VERSION 5.7 ;
  NOWIREEXTENSIONATPIN ON ;
  DIVIDERCHAR "/" ;
  BUSBITCHARS "[]" ;
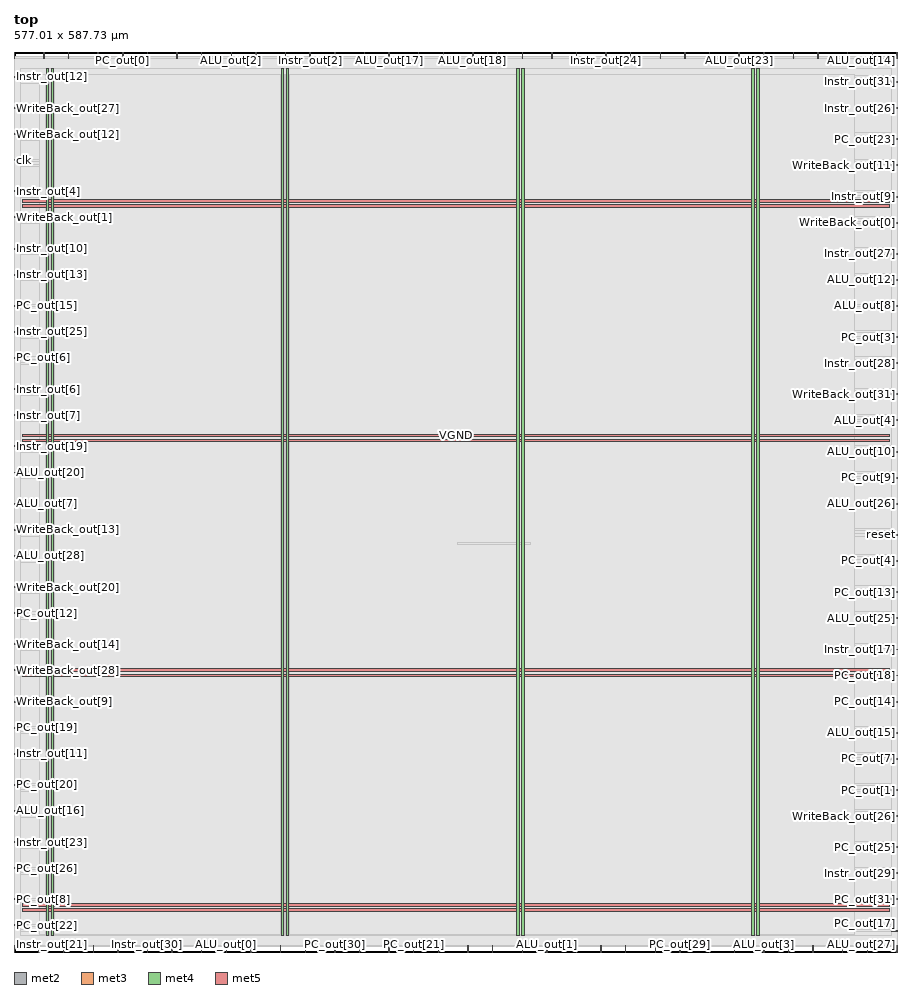
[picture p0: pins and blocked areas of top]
MACRO top
  CLASS BLOCK ;
  FOREIGN top ;
  ORIGIN 0.000 0.000 ;
  SIZE 577.010 BY 587.730 ;
  PIN ALU_out[0]
    DIRECTION OUTPUT TRISTATE ;
    USE SIGNAL ;
    ANTENNADIFFAREA 0.795200 ;
    PORT
      LAYER met2 ;
        RECT 138.550 0.000 138.830 4.000 ;
    END
  END ALU_out[0]
  PIN ALU_out[10]
    DIRECTION OUTPUT TRISTATE ;
    USE SIGNAL ;
    ANTENNADIFFAREA 0.445500 ;
    PORT
      LAYER met3 ;
        RECT 573.010 326.440 577.010 327.040 ;
    END
  END ALU_out[10]
  PIN ALU_out[11]
    DIRECTION OUTPUT TRISTATE ;
    USE SIGNAL ;
    ANTENNADIFFAREA 0.795200 ;
    PORT
      LAYER met2 ;
        RECT 541.050 0.000 541.330 4.000 ;
    END
  END ALU_out[11]
  PIN ALU_out[12]
    DIRECTION OUTPUT TRISTATE ;
    USE SIGNAL ;
    ANTENNADIFFAREA 0.445500 ;
    PORT
      LAYER met3 ;
        RECT 573.010 438.640 577.010 439.240 ;
    END
  END ALU_out[12]
  PIN ALU_out[13]
    DIRECTION OUTPUT TRISTATE ;
    USE SIGNAL ;
    ANTENNADIFFAREA 0.795200 ;
    PORT
      LAYER met2 ;
        RECT 244.810 0.000 245.090 4.000 ;
    END
  END ALU_out[13]
  PIN ALU_out[14]
    DIRECTION OUTPUT TRISTATE ;
    USE SIGNAL ;
    ANTENNADIFFAREA 0.795200 ;
    PORT
      LAYER met2 ;
        RECT 576.470 583.730 576.750 587.730 ;
    END
  END ALU_out[14]
  PIN ALU_out[15]
    DIRECTION OUTPUT TRISTATE ;
    USE SIGNAL ;
    ANTENNADIFFAREA 0.795200 ;
    PORT
      LAYER met3 ;
        RECT 573.010 142.840 577.010 143.440 ;
    END
  END ALU_out[15]
  PIN ALU_out[16]
    DIRECTION OUTPUT TRISTATE ;
    USE SIGNAL ;
    ANTENNADIFFAREA 0.795200 ;
    PORT
      LAYER met3 ;
        RECT 0.000 91.840 4.000 92.440 ;
    END
  END ALU_out[16]
  PIN ALU_out[17]
    DIRECTION OUTPUT TRISTATE ;
    USE SIGNAL ;
    ANTENNADIFFAREA 0.445500 ;
    PORT
      LAYER met2 ;
        RECT 244.810 583.730 245.090 587.730 ;
    END
  END ALU_out[17]
  PIN ALU_out[18]
    DIRECTION OUTPUT TRISTATE ;
    USE SIGNAL ;
    ANTENNADIFFAREA 0.445500 ;
    PORT
      LAYER met2 ;
        RECT 299.550 583.730 299.830 587.730 ;
    END
  END ALU_out[18]
  PIN ALU_out[19]
    DIRECTION OUTPUT TRISTATE ;
    USE SIGNAL ;
    ANTENNADIFFAREA 0.795200 ;
    PORT
      LAYER met2 ;
        RECT 508.850 583.730 509.130 587.730 ;
    END
  END ALU_out[19]
  PIN ALU_out[1]
    DIRECTION OUTPUT TRISTATE ;
    USE SIGNAL ;
    ANTENNADIFFAREA 0.795200 ;
    PORT
      LAYER met2 ;
        RECT 347.850 0.000 348.130 4.000 ;
    END
  END ALU_out[1]
  PIN ALU_out[20]
    DIRECTION OUTPUT TRISTATE ;
    USE SIGNAL ;
    ANTENNADIFFAREA 0.795200 ;
    PORT
      LAYER met3 ;
        RECT 0.000 312.840 4.000 313.440 ;
    END
  END ALU_out[20]
  PIN ALU_out[21]
    DIRECTION OUTPUT TRISTATE ;
    USE SIGNAL ;
    ANTENNADIFFAREA 0.445500 ;
    PORT
      LAYER met2 ;
        RECT 560.370 583.730 560.650 587.730 ;
    END
  END ALU_out[21]
  PIN ALU_out[22]
    DIRECTION OUTPUT TRISTATE ;
    USE SIGNAL ;
    ANTENNADIFFAREA 0.795200 ;
    PORT
      LAYER met2 ;
        RECT 54.830 583.730 55.110 587.730 ;
    END
  END ALU_out[22]
  PIN ALU_out[23]
    DIRECTION OUTPUT TRISTATE ;
    USE SIGNAL ;
    ANTENNADIFFAREA 0.445500 ;
    PORT
      LAYER met2 ;
        RECT 473.430 583.730 473.710 587.730 ;
    END
  END ALU_out[23]
  PIN ALU_out[24]
    DIRECTION OUTPUT TRISTATE ;
    USE SIGNAL ;
    ANTENNADIFFAREA 0.795200 ;
    PORT
      LAYER met2 ;
        RECT 228.710 583.730 228.990 587.730 ;
    END
  END ALU_out[24]
  PIN ALU_out[25]
    DIRECTION OUTPUT TRISTATE ;
    USE SIGNAL ;
    ANTENNADIFFAREA 0.445500 ;
    PORT
      LAYER met3 ;
        RECT 573.010 217.640 577.010 218.240 ;
    END
  END ALU_out[25]
  PIN ALU_out[26]
    DIRECTION OUTPUT TRISTATE ;
    USE SIGNAL ;
    ANTENNADIFFAREA 0.795200 ;
    PORT
      LAYER met3 ;
        RECT 573.010 292.440 577.010 293.040 ;
    END
  END ALU_out[26]
  PIN ALU_out[27]
    DIRECTION OUTPUT TRISTATE ;
    USE SIGNAL ;
    ANTENNADIFFAREA 0.795200 ;
    PORT
      LAYER met2 ;
        RECT 557.150 0.000 557.430 4.000 ;
    END
  END ALU_out[27]
  PIN ALU_out[28]
    DIRECTION OUTPUT TRISTATE ;
    USE SIGNAL ;
    ANTENNADIFFAREA 0.795200 ;
    PORT
      LAYER met3 ;
        RECT 0.000 258.440 4.000 259.040 ;
    END
  END ALU_out[28]
  PIN ALU_out[29]
    DIRECTION OUTPUT TRISTATE ;
    USE SIGNAL ;
    ANTENNADIFFAREA 0.795200 ;
    PORT
      LAYER met2 ;
        RECT 225.490 0.000 225.770 4.000 ;
    END
  END ALU_out[29]
  PIN ALU_out[2]
    DIRECTION OUTPUT TRISTATE ;
    USE SIGNAL ;
    ANTENNADIFFAREA 0.445500 ;
    PORT
      LAYER met2 ;
        RECT 141.770 583.730 142.050 587.730 ;
    END
  END ALU_out[2]
  PIN ALU_out[30]
    DIRECTION OUTPUT TRISTATE ;
    USE SIGNAL ;
    ANTENNADIFFAREA 0.795200 ;
    PORT
      LAYER met2 ;
        RECT 470.210 0.000 470.490 4.000 ;
    END
  END ALU_out[30]
  PIN ALU_out[31]
    DIRECTION OUTPUT TRISTATE ;
    USE SIGNAL ;
    ANTENNADIFFAREA 0.795200 ;
    PORT
      LAYER met2 ;
        RECT 154.650 0.000 154.930 4.000 ;
    END
  END ALU_out[31]
  PIN ALU_out[3]
    DIRECTION OUTPUT TRISTATE ;
    USE SIGNAL ;
    ANTENNADIFFAREA 0.795200 ;
    PORT
      LAYER met2 ;
        RECT 489.530 0.000 489.810 4.000 ;
    END
  END ALU_out[3]
  PIN ALU_out[4]
    DIRECTION OUTPUT TRISTATE ;
    USE SIGNAL ;
    ANTENNADIFFAREA 0.445500 ;
    PORT
      LAYER met3 ;
        RECT 573.010 346.840 577.010 347.440 ;
    END
  END ALU_out[4]
  PIN ALU_out[5]
    DIRECTION OUTPUT TRISTATE ;
    USE SIGNAL ;
    ANTENNADIFFAREA 0.795200 ;
    PORT
      LAYER met2 ;
        RECT 367.170 0.000 367.450 4.000 ;
    END
  END ALU_out[5]
  PIN ALU_out[6]
    DIRECTION OUTPUT TRISTATE ;
    USE SIGNAL ;
    ANTENNADIFFAREA 0.795200 ;
    PORT
      LAYER met2 ;
        RECT 418.690 0.000 418.970 4.000 ;
    END
  END ALU_out[6]
  PIN ALU_out[7]
    DIRECTION OUTPUT TRISTATE ;
    USE SIGNAL ;
    ANTENNADIFFAREA 0.795200 ;
    PORT
      LAYER met3 ;
        RECT 0.000 292.440 4.000 293.040 ;
    END
  END ALU_out[7]
  PIN ALU_out[8]
    DIRECTION OUTPUT TRISTATE ;
    USE SIGNAL ;
    ANTENNADIFFAREA 0.445500 ;
    PORT
      LAYER met3 ;
        RECT 573.010 421.640 577.010 422.240 ;
    END
  END ALU_out[8]
  PIN ALU_out[9]
    DIRECTION OUTPUT TRISTATE ;
    USE SIGNAL ;
    ANTENNADIFFAREA 0.795200 ;
    PORT
      LAYER met2 ;
        RECT 157.870 583.730 158.150 587.730 ;
    END
  END ALU_out[9]
  PIN Instr_out[0]
    DIRECTION OUTPUT TRISTATE ;
    USE SIGNAL ;
    PORT
      LAYER met2 ;
        RECT 576.470 0.000 576.750 4.000 ;
    END
  END Instr_out[0]
  PIN Instr_out[10]
    DIRECTION OUTPUT TRISTATE ;
    USE SIGNAL ;
    PORT
      LAYER met3 ;
        RECT 0.000 459.040 4.000 459.640 ;
    END
  END Instr_out[10]
  PIN Instr_out[11]
    DIRECTION OUTPUT TRISTATE ;
    USE SIGNAL ;
    PORT
      LAYER met3 ;
        RECT 0.000 129.240 4.000 129.840 ;
    END
  END Instr_out[11]
  PIN Instr_out[12]
    DIRECTION OUTPUT TRISTATE ;
    USE SIGNAL ;
    ANTENNADIFFAREA 0.795200 ;
    PORT
      LAYER met3 ;
        RECT 0.000 571.240 4.000 571.840 ;
    END
  END Instr_out[12]
  PIN Instr_out[13]
    DIRECTION OUTPUT TRISTATE ;
    USE SIGNAL ;
    ANTENNADIFFAREA 0.795200 ;
    PORT
      LAYER met3 ;
        RECT 0.000 442.040 4.000 442.640 ;
    END
  END Instr_out[13]
  PIN Instr_out[14]
    DIRECTION OUTPUT TRISTATE ;
    USE SIGNAL ;
    ANTENNADIFFAREA 0.795200 ;
    PORT
      LAYER met2 ;
        RECT 544.270 583.730 544.550 587.730 ;
    END
  END Instr_out[14]
  PIN Instr_out[15]
    DIRECTION OUTPUT TRISTATE ;
    USE SIGNAL ;
    ANTENNADIFFAREA 0.795200 ;
    PORT
      LAYER met2 ;
        RECT 489.530 583.730 489.810 587.730 ;
    END
  END Instr_out[15]
  PIN Instr_out[16]
    DIRECTION OUTPUT TRISTATE ;
    USE SIGNAL ;
    ANTENNADIFFAREA 0.795200 ;
    PORT
      LAYER met2 ;
        RECT 122.450 583.730 122.730 587.730 ;
    END
  END Instr_out[16]
  PIN Instr_out[17]
    DIRECTION OUTPUT TRISTATE ;
    USE SIGNAL ;
    PORT
      LAYER met3 ;
        RECT 573.010 197.240 577.010 197.840 ;
    END
  END Instr_out[17]
  PIN Instr_out[18]
    DIRECTION OUTPUT TRISTATE ;
    USE SIGNAL ;
    PORT
      LAYER met2 ;
        RECT 173.970 0.000 174.250 4.000 ;
    END
  END Instr_out[18]
  PIN Instr_out[19]
    DIRECTION OUTPUT TRISTATE ;
    USE SIGNAL ;
    PORT
      LAYER met3 ;
        RECT 0.000 329.840 4.000 330.440 ;
    END
  END Instr_out[19]
  PIN Instr_out[1]
    DIRECTION OUTPUT TRISTATE ;
    USE SIGNAL ;
    PORT
      LAYER met2 ;
        RECT 87.030 583.730 87.310 587.730 ;
    END
  END Instr_out[1]
  PIN Instr_out[20]
    DIRECTION OUTPUT TRISTATE ;
    USE SIGNAL ;
    ANTENNADIFFAREA 0.795200 ;
    PORT
      LAYER met2 ;
        RECT 315.650 583.730 315.930 587.730 ;
    END
  END Instr_out[20]
  PIN Instr_out[21]
    DIRECTION OUTPUT TRISTATE ;
    USE SIGNAL ;
    ANTENNADIFFAREA 0.795200 ;
    PORT
      LAYER met2 ;
        RECT 16.190 0.000 16.470 4.000 ;
    END
  END Instr_out[21]
  PIN Instr_out[22]
    DIRECTION OUTPUT TRISTATE ;
    USE SIGNAL ;
    ANTENNADIFFAREA 0.445500 ;
    PORT
      LAYER met2 ;
        RECT 402.590 583.730 402.870 587.730 ;
    END
  END Instr_out[22]
  PIN Instr_out[23]
    DIRECTION OUTPUT TRISTATE ;
    USE SIGNAL ;
    ANTENNADIFFAREA 0.795200 ;
    PORT
      LAYER met3 ;
        RECT 0.000 71.440 4.000 72.040 ;
    END
  END Instr_out[23]
  PIN Instr_out[24]
    DIRECTION OUTPUT TRISTATE ;
    USE SIGNAL ;
    PORT
      LAYER met2 ;
        RECT 386.490 583.730 386.770 587.730 ;
    END
  END Instr_out[24]
  PIN Instr_out[25]
    DIRECTION OUTPUT TRISTATE ;
    USE SIGNAL ;
    PORT
      LAYER met3 ;
        RECT 0.000 404.640 4.000 405.240 ;
    END
  END Instr_out[25]
  PIN Instr_out[26]
    DIRECTION OUTPUT TRISTATE ;
    USE SIGNAL ;
    PORT
      LAYER met3 ;
        RECT 573.010 550.840 577.010 551.440 ;
    END
  END Instr_out[26]
  PIN Instr_out[27]
    DIRECTION OUTPUT TRISTATE ;
    USE SIGNAL ;
    PORT
      LAYER met3 ;
        RECT 573.010 455.640 577.010 456.240 ;
    END
  END Instr_out[27]
  PIN Instr_out[28]
    DIRECTION OUTPUT TRISTATE ;
    USE SIGNAL ;
    PORT
      LAYER met3 ;
        RECT 573.010 384.240 577.010 384.840 ;
    END
  END Instr_out[28]
  PIN Instr_out[29]
    DIRECTION OUTPUT TRISTATE ;
    USE SIGNAL ;
    PORT
      LAYER met3 ;
        RECT 573.010 51.040 577.010 51.640 ;
    END
  END Instr_out[29]
  PIN Instr_out[2]
    DIRECTION OUTPUT TRISTATE ;
    USE SIGNAL ;
    PORT
      LAYER met2 ;
        RECT 193.290 583.730 193.570 587.730 ;
    END
  END Instr_out[2]
  PIN Instr_out[30]
    DIRECTION OUTPUT TRISTATE ;
    USE SIGNAL ;
    ANTENNADIFFAREA 0.795200 ;
    PORT
      LAYER met2 ;
        RECT 87.030 0.000 87.310 4.000 ;
    END
  END Instr_out[30]
  PIN Instr_out[31]
    DIRECTION OUTPUT TRISTATE ;
    USE SIGNAL ;
    PORT
      LAYER met3 ;
        RECT 573.010 567.840 577.010 568.440 ;
    END
  END Instr_out[31]
  PIN Instr_out[3]
    DIRECTION OUTPUT TRISTATE ;
    USE SIGNAL ;
    PORT
      LAYER met2 ;
        RECT 296.330 0.000 296.610 4.000 ;
    END
  END Instr_out[3]
  PIN Instr_out[4]
    DIRECTION OUTPUT TRISTATE ;
    USE SIGNAL ;
    ANTENNADIFFAREA 0.795200 ;
    PORT
      LAYER met3 ;
        RECT 0.000 496.440 4.000 497.040 ;
    END
  END Instr_out[4]
  PIN Instr_out[5]
    DIRECTION OUTPUT TRISTATE ;
    USE SIGNAL ;
    ANTENNADIFFAREA 0.795200 ;
    PORT
      LAYER met2 ;
        RECT 351.070 583.730 351.350 587.730 ;
    END
  END Instr_out[5]
  PIN Instr_out[6]
    DIRECTION OUTPUT TRISTATE ;
    USE SIGNAL ;
    ANTENNADIFFAREA 0.795200 ;
    PORT
      LAYER met3 ;
        RECT 0.000 367.240 4.000 367.840 ;
    END
  END Instr_out[6]
  PIN Instr_out[7]
    DIRECTION OUTPUT TRISTATE ;
    USE SIGNAL ;
    ANTENNADIFFAREA 0.795200 ;
    PORT
      LAYER met3 ;
        RECT 0.000 350.240 4.000 350.840 ;
    END
  END Instr_out[7]
  PIN Instr_out[8]
    DIRECTION OUTPUT TRISTATE ;
    USE SIGNAL ;
    ANTENNADIFFAREA 0.795200 ;
    PORT
      LAYER met2 ;
        RECT 35.510 583.730 35.790 587.730 ;
    END
  END Instr_out[8]
  PIN Instr_out[9]
    DIRECTION OUTPUT TRISTATE ;
    USE SIGNAL ;
    ANTENNADIFFAREA 0.445500 ;
    PORT
      LAYER met3 ;
        RECT 573.010 493.040 577.010 493.640 ;
    END
  END Instr_out[9]
  PIN PC_out[0]
    DIRECTION OUTPUT TRISTATE ;
    USE SIGNAL ;
    ANTENNADIFFAREA 0.445500 ;
    PORT
      LAYER met2 ;
        RECT 70.930 583.730 71.210 587.730 ;
    END
  END PC_out[0]
  PIN PC_out[10]
    DIRECTION OUTPUT TRISTATE ;
    USE SIGNAL ;
    ANTENNADIFFAREA 0.445500 ;
    PORT
      LAYER met2 ;
        RECT 209.390 583.730 209.670 587.730 ;
    END
  END PC_out[10]
  PIN PC_out[11]
    DIRECTION OUTPUT TRISTATE ;
    USE SIGNAL ;
    ANTENNADIFFAREA 0.445500 ;
    PORT
      LAYER met2 ;
        RECT 264.130 583.730 264.410 587.730 ;
    END
  END PC_out[11]
  PIN PC_out[12]
    DIRECTION OUTPUT TRISTATE ;
    USE SIGNAL ;
    ANTENNADIFFAREA 0.795200 ;
    PORT
      LAYER met3 ;
        RECT 0.000 221.040 4.000 221.640 ;
    END
  END PC_out[12]
  PIN PC_out[13]
    DIRECTION OUTPUT TRISTATE ;
    USE SIGNAL ;
    ANTENNADIFFAREA 0.445500 ;
    PORT
      LAYER met3 ;
        RECT 573.010 234.640 577.010 235.240 ;
    END
  END PC_out[13]
  PIN PC_out[14]
    DIRECTION OUTPUT TRISTATE ;
    USE SIGNAL ;
    ANTENNADIFFAREA 0.445500 ;
    PORT
      LAYER met3 ;
        RECT 573.010 163.240 577.010 163.840 ;
    END
  END PC_out[14]
  PIN PC_out[15]
    DIRECTION OUTPUT TRISTATE ;
    USE SIGNAL ;
    ANTENNADIFFAREA 0.795200 ;
    PORT
      LAYER met3 ;
        RECT 0.000 421.640 4.000 422.240 ;
    END
  END PC_out[15]
  PIN PC_out[16]
    DIRECTION OUTPUT TRISTATE ;
    USE SIGNAL ;
    ANTENNADIFFAREA 0.795200 ;
    PORT
      LAYER met2 ;
        RECT 51.610 0.000 51.890 4.000 ;
    END
  END PC_out[16]
  PIN PC_out[17]
    DIRECTION OUTPUT TRISTATE ;
    USE SIGNAL ;
    ANTENNADIFFAREA 0.445500 ;
    PORT
      LAYER met3 ;
        RECT 573.010 13.640 577.010 14.240 ;
    END
  END PC_out[17]
  PIN PC_out[18]
    DIRECTION OUTPUT TRISTATE ;
    USE SIGNAL ;
    ANTENNADIFFAREA 0.445500 ;
    PORT
      LAYER met3 ;
        RECT 573.010 180.240 577.010 180.840 ;
    END
  END PC_out[18]
  PIN PC_out[19]
    DIRECTION OUTPUT TRISTATE ;
    USE SIGNAL ;
    ANTENNADIFFAREA 0.795200 ;
    PORT
      LAYER met3 ;
        RECT 0.000 146.240 4.000 146.840 ;
    END
  END PC_out[19]
  PIN PC_out[1]
    DIRECTION OUTPUT TRISTATE ;
    USE SIGNAL ;
    ANTENNADIFFAREA 0.445500 ;
    PORT
      LAYER met3 ;
        RECT 573.010 105.440 577.010 106.040 ;
    END
  END PC_out[1]
  PIN PC_out[20]
    DIRECTION OUTPUT TRISTATE ;
    USE SIGNAL ;
    ANTENNADIFFAREA 0.795200 ;
    PORT
      LAYER met3 ;
        RECT 0.000 108.840 4.000 109.440 ;
    END
  END PC_out[20]
  PIN PC_out[21]
    DIRECTION OUTPUT TRISTATE ;
    USE SIGNAL ;
    ANTENNADIFFAREA 0.795200 ;
    PORT
      LAYER met2 ;
        RECT 260.910 0.000 261.190 4.000 ;
    END
  END PC_out[21]
  PIN PC_out[22]
    DIRECTION OUTPUT TRISTATE ;
    USE SIGNAL ;
    ANTENNADIFFAREA 0.795200 ;
    PORT
      LAYER met3 ;
        RECT 0.000 17.040 4.000 17.640 ;
    END
  END PC_out[22]
  PIN PC_out[23]
    DIRECTION OUTPUT TRISTATE ;
    USE SIGNAL ;
    ANTENNADIFFAREA 0.795200 ;
    PORT
      LAYER met3 ;
        RECT 573.010 530.440 577.010 531.040 ;
    END
  END PC_out[23]
  PIN PC_out[24]
    DIRECTION OUTPUT TRISTATE ;
    USE SIGNAL ;
    ANTENNADIFFAREA 0.795200 ;
    PORT
      LAYER met2 ;
        RECT 122.450 0.000 122.730 4.000 ;
    END
  END PC_out[24]
  PIN PC_out[25]
    DIRECTION OUTPUT TRISTATE ;
    USE SIGNAL ;
    ANTENNADIFFAREA 0.795200 ;
    PORT
      LAYER met3 ;
        RECT 573.010 68.040 577.010 68.640 ;
    END
  END PC_out[25]
  PIN PC_out[26]
    DIRECTION OUTPUT TRISTATE ;
    USE SIGNAL ;
    ANTENNADIFFAREA 0.795200 ;
    PORT
      LAYER met3 ;
        RECT 0.000 54.440 4.000 55.040 ;
    END
  END PC_out[26]
  PIN PC_out[27]
    DIRECTION OUTPUT TRISTATE ;
    USE SIGNAL ;
    ANTENNADIFFAREA 0.795200 ;
    PORT
      LAYER met2 ;
        RECT 521.730 0.000 522.010 4.000 ;
    END
  END PC_out[27]
  PIN PC_out[28]
    DIRECTION OUTPUT TRISTATE ;
    USE SIGNAL ;
    ANTENNADIFFAREA 0.445500 ;
    PORT
      LAYER met2 ;
        RECT 280.230 583.730 280.510 587.730 ;
    END
  END PC_out[28]
  PIN PC_out[29]
    DIRECTION OUTPUT TRISTATE ;
    USE SIGNAL ;
    ANTENNADIFFAREA 0.795200 ;
    PORT
      LAYER met2 ;
        RECT 434.790 0.000 435.070 4.000 ;
    END
  END PC_out[29]
  PIN PC_out[2]
    DIRECTION OUTPUT TRISTATE ;
    USE SIGNAL ;
    ANTENNADIFFAREA 0.795200 ;
    PORT
      LAYER met2 ;
        RECT 67.710 0.000 67.990 4.000 ;
    END
  END PC_out[2]
  PIN PC_out[30]
    DIRECTION OUTPUT TRISTATE ;
    USE SIGNAL ;
    ANTENNADIFFAREA 0.795200 ;
    PORT
      LAYER met2 ;
        RECT 209.390 0.000 209.670 4.000 ;
    END
  END PC_out[30]
  PIN PC_out[31]
    DIRECTION OUTPUT TRISTATE ;
    USE SIGNAL ;
    ANTENNADIFFAREA 0.795200 ;
    PORT
      LAYER met3 ;
        RECT 573.010 34.040 577.010 34.640 ;
    END
  END PC_out[31]
  PIN PC_out[3]
    DIRECTION OUTPUT TRISTATE ;
    USE SIGNAL ;
    ANTENNADIFFAREA 0.445500 ;
    PORT
      LAYER met3 ;
        RECT 573.010 401.240 577.010 401.840 ;
    END
  END PC_out[3]
  PIN PC_out[4]
    DIRECTION OUTPUT TRISTATE ;
    USE SIGNAL ;
    ANTENNADIFFAREA 0.445500 ;
    PORT
      LAYER met3 ;
        RECT 573.010 255.040 577.010 255.640 ;
    END
  END PC_out[4]
  PIN PC_out[5]
    DIRECTION OUTPUT TRISTATE ;
    USE SIGNAL ;
    ANTENNADIFFAREA 0.795200 ;
    PORT
      LAYER met2 ;
        RECT 454.110 0.000 454.390 4.000 ;
    END
  END PC_out[5]
  PIN PC_out[6]
    DIRECTION OUTPUT TRISTATE ;
    USE SIGNAL ;
    ANTENNADIFFAREA 0.795200 ;
    PORT
      LAYER met3 ;
        RECT 0.000 387.640 4.000 388.240 ;
    END
  END PC_out[6]
  PIN PC_out[7]
    DIRECTION OUTPUT TRISTATE ;
    USE SIGNAL ;
    ANTENNADIFFAREA 0.445500 ;
    PORT
      LAYER met3 ;
        RECT 573.010 125.840 577.010 126.440 ;
    END
  END PC_out[7]
  PIN PC_out[8]
    DIRECTION OUTPUT TRISTATE ;
    USE SIGNAL ;
    ANTENNADIFFAREA 0.795200 ;
    PORT
      LAYER met3 ;
        RECT 0.000 34.040 4.000 34.640 ;
    END
  END PC_out[8]
  PIN PC_out[9]
    DIRECTION OUTPUT TRISTATE ;
    USE SIGNAL ;
    ANTENNADIFFAREA 0.795200 ;
    PORT
      LAYER met3 ;
        RECT 573.010 309.440 577.010 310.040 ;
    END
  END PC_out[9]
  PIN VGND
    DIRECTION INOUT ;
    USE GROUND ;
    PORT
      LAYER met4 ;
        RECT 24.340 10.640 25.940 576.880 ;
    END
    PORT
      LAYER met4 ;
        RECT 177.940 10.640 179.540 576.880 ;
    END
    PORT
      LAYER met4 ;
        RECT 331.540 10.640 333.140 576.880 ;
    END
    PORT
      LAYER met4 ;
        RECT 485.140 10.640 486.740 576.880 ;
    END
    PORT
      LAYER met5 ;
        RECT 5.280 30.030 571.560 31.630 ;
    END
    PORT
      LAYER met5 ;
        RECT 5.280 183.210 571.560 184.810 ;
    END
    PORT
      LAYER met5 ;
        RECT 5.280 336.390 571.560 337.990 ;
    END
    PORT
      LAYER met5 ;
        RECT 5.280 489.570 571.560 491.170 ;
    END
  END VGND
  PIN VPWR
    DIRECTION INOUT ;
    USE POWER ;
    PORT
      LAYER met4 ;
        RECT 21.040 10.640 22.640 576.880 ;
    END
    PORT
      LAYER met4 ;
        RECT 174.640 10.640 176.240 576.880 ;
    END
    PORT
      LAYER met4 ;
        RECT 328.240 10.640 329.840 576.880 ;
    END
    PORT
      LAYER met4 ;
        RECT 481.840 10.640 483.440 576.880 ;
    END
    PORT
      LAYER met5 ;
        RECT 5.280 26.730 571.560 28.330 ;
    END
    PORT
      LAYER met5 ;
        RECT 5.280 179.910 571.560 181.510 ;
    END
    PORT
      LAYER met5 ;
        RECT 5.280 333.090 571.560 334.690 ;
    END
    PORT
      LAYER met5 ;
        RECT 5.280 486.270 571.560 487.870 ;
    END
  END VPWR
  PIN WriteBack_out[0]
    DIRECTION OUTPUT TRISTATE ;
    USE SIGNAL ;
    ANTENNADIFFAREA 0.445500 ;
    PORT
      LAYER met3 ;
        RECT 573.010 476.040 577.010 476.640 ;
    END
  END WriteBack_out[0]
  PIN WriteBack_out[10]
    DIRECTION OUTPUT TRISTATE ;
    USE SIGNAL ;
    ANTENNADIFFAREA 0.795200 ;
    PORT
      LAYER met2 ;
        RECT 505.630 0.000 505.910 4.000 ;
    END
  END WriteBack_out[10]
  PIN WriteBack_out[11]
    DIRECTION OUTPUT TRISTATE ;
    USE SIGNAL ;
    ANTENNADIFFAREA 0.445500 ;
    PORT
      LAYER met3 ;
        RECT 573.010 513.440 577.010 514.040 ;
    END
  END WriteBack_out[11]
  PIN WriteBack_out[12]
    DIRECTION OUTPUT TRISTATE ;
    USE SIGNAL ;
    ANTENNADIFFAREA 0.795200 ;
    PORT
      LAYER met3 ;
        RECT 0.000 533.840 4.000 534.440 ;
    END
  END WriteBack_out[12]
  PIN WriteBack_out[13]
    DIRECTION OUTPUT TRISTATE ;
    USE SIGNAL ;
    ANTENNADIFFAREA 0.795200 ;
    PORT
      LAYER met3 ;
        RECT 0.000 275.440 4.000 276.040 ;
    END
  END WriteBack_out[13]
  PIN WriteBack_out[14]
    DIRECTION OUTPUT TRISTATE ;
    USE SIGNAL ;
    ANTENNADIFFAREA 0.795200 ;
    PORT
      LAYER met3 ;
        RECT 0.000 200.640 4.000 201.240 ;
    END
  END WriteBack_out[14]
  PIN WriteBack_out[15]
    DIRECTION OUTPUT TRISTATE ;
    USE SIGNAL ;
    ANTENNADIFFAREA 0.795200 ;
    PORT
      LAYER met2 ;
        RECT 0.090 0.000 0.370 4.000 ;
    END
  END WriteBack_out[15]
  PIN WriteBack_out[16]
    DIRECTION OUTPUT TRISTATE ;
    USE SIGNAL ;
    ANTENNADIFFAREA 0.795200 ;
    PORT
      LAYER met2 ;
        RECT 383.270 0.000 383.550 4.000 ;
    END
  END WriteBack_out[16]
  PIN WriteBack_out[17]
    DIRECTION OUTPUT TRISTATE ;
    USE SIGNAL ;
    ANTENNADIFFAREA 0.795200 ;
    PORT
      LAYER met2 ;
        RECT 0.090 583.730 0.370 587.730 ;
    END
  END WriteBack_out[17]
  PIN WriteBack_out[18]
    DIRECTION OUTPUT TRISTATE ;
    USE SIGNAL ;
    ANTENNADIFFAREA 0.445500 ;
    PORT
      LAYER met2 ;
        RECT 177.190 583.730 177.470 587.730 ;
    END
  END WriteBack_out[18]
  PIN WriteBack_out[19]
    DIRECTION OUTPUT TRISTATE ;
    USE SIGNAL ;
    ANTENNADIFFAREA 0.445500 ;
    PORT
      LAYER met2 ;
        RECT 367.170 583.730 367.450 587.730 ;
    END
  END WriteBack_out[19]
  PIN WriteBack_out[1]
    DIRECTION OUTPUT TRISTATE ;
    USE SIGNAL ;
    ANTENNADIFFAREA 0.795200 ;
    PORT
      LAYER met3 ;
        RECT 0.000 479.440 4.000 480.040 ;
    END
  END WriteBack_out[1]
  PIN WriteBack_out[20]
    DIRECTION OUTPUT TRISTATE ;
    USE SIGNAL ;
    ANTENNADIFFAREA 0.795200 ;
    PORT
      LAYER met3 ;
        RECT 0.000 238.040 4.000 238.640 ;
    END
  END WriteBack_out[20]
  PIN WriteBack_out[21]
    DIRECTION OUTPUT TRISTATE ;
    USE SIGNAL ;
    ANTENNADIFFAREA 0.795200 ;
    PORT
      LAYER met2 ;
        RECT 32.290 0.000 32.570 4.000 ;
    END
  END WriteBack_out[21]
  PIN WriteBack_out[22]
    DIRECTION OUTPUT TRISTATE ;
    USE SIGNAL ;
    ANTENNADIFFAREA 0.795200 ;
    PORT
      LAYER met2 ;
        RECT 454.110 583.730 454.390 587.730 ;
    END
  END WriteBack_out[22]
  PIN WriteBack_out[23]
    DIRECTION OUTPUT TRISTATE ;
    USE SIGNAL ;
    ANTENNADIFFAREA 0.795200 ;
    PORT
      LAYER met2 ;
        RECT 331.750 583.730 332.030 587.730 ;
    END
  END WriteBack_out[23]
  PIN WriteBack_out[24]
    DIRECTION OUTPUT TRISTATE ;
    USE SIGNAL ;
    ANTENNADIFFAREA 0.795200 ;
    PORT
      LAYER met2 ;
        RECT 277.010 0.000 277.290 4.000 ;
    END
  END WriteBack_out[24]
  PIN WriteBack_out[25]
    DIRECTION OUTPUT TRISTATE ;
    USE SIGNAL ;
    ANTENNADIFFAREA 0.795200 ;
    PORT
      LAYER met2 ;
        RECT 524.950 583.730 525.230 587.730 ;
    END
  END WriteBack_out[25]
  PIN WriteBack_out[26]
    DIRECTION OUTPUT TRISTATE ;
    USE SIGNAL ;
    ANTENNADIFFAREA 0.795200 ;
    PORT
      LAYER met3 ;
        RECT 573.010 88.440 577.010 89.040 ;
    END
  END WriteBack_out[26]
  PIN WriteBack_out[27]
    DIRECTION OUTPUT TRISTATE ;
    USE SIGNAL ;
    ANTENNADIFFAREA 0.795200 ;
    PORT
      LAYER met3 ;
        RECT 0.000 550.840 4.000 551.440 ;
    END
  END WriteBack_out[27]
  PIN WriteBack_out[28]
    DIRECTION OUTPUT TRISTATE ;
    USE SIGNAL ;
    ANTENNADIFFAREA 0.795200 ;
    PORT
      LAYER met3 ;
        RECT 0.000 183.640 4.000 184.240 ;
    END
  END WriteBack_out[28]
  PIN WriteBack_out[29]
    DIRECTION OUTPUT TRISTATE ;
    USE SIGNAL ;
    ANTENNADIFFAREA 0.795200 ;
    PORT
      LAYER met2 ;
        RECT 103.130 0.000 103.410 4.000 ;
    END
  END WriteBack_out[29]
  PIN WriteBack_out[2]
    DIRECTION OUTPUT TRISTATE ;
    USE SIGNAL ;
    ANTENNADIFFAREA 0.795200 ;
    PORT
      LAYER met2 ;
        RECT 190.070 0.000 190.350 4.000 ;
    END
  END WriteBack_out[2]
  PIN WriteBack_out[30]
    DIRECTION OUTPUT TRISTATE ;
    USE SIGNAL ;
    ANTENNADIFFAREA 0.891000 ;
    PORT
      LAYER met2 ;
        RECT 312.430 0.000 312.710 4.000 ;
    END
  END WriteBack_out[30]
  PIN WriteBack_out[31]
    DIRECTION OUTPUT TRISTATE ;
    USE SIGNAL ;
    ANTENNADIFFAREA 0.445500 ;
    PORT
      LAYER met3 ;
        RECT 573.010 363.840 577.010 364.440 ;
    END
  END WriteBack_out[31]
  PIN WriteBack_out[3]
    DIRECTION OUTPUT TRISTATE ;
    USE SIGNAL ;
    ANTENNADIFFAREA 0.795200 ;
    PORT
      LAYER met2 ;
        RECT 331.750 0.000 332.030 4.000 ;
    END
  END WriteBack_out[3]
  PIN WriteBack_out[4]
    DIRECTION OUTPUT TRISTATE ;
    USE SIGNAL ;
    ANTENNADIFFAREA 0.445500 ;
    PORT
      LAYER met2 ;
        RECT 438.010 583.730 438.290 587.730 ;
    END
  END WriteBack_out[4]
  PIN WriteBack_out[5]
    DIRECTION OUTPUT TRISTATE ;
    USE SIGNAL ;
    ANTENNADIFFAREA 0.445500 ;
    PORT
      LAYER met2 ;
        RECT 421.910 583.730 422.190 587.730 ;
    END
  END WriteBack_out[5]
  PIN WriteBack_out[6]
    DIRECTION OUTPUT TRISTATE ;
    USE SIGNAL ;
    ANTENNADIFFAREA 0.795200 ;
    PORT
      LAYER met2 ;
        RECT 19.410 583.730 19.690 587.730 ;
    END
  END WriteBack_out[6]
  PIN WriteBack_out[7]
    DIRECTION OUTPUT TRISTATE ;
    USE SIGNAL ;
    ANTENNADIFFAREA 0.445500 ;
    PORT
      LAYER met2 ;
        RECT 106.350 583.730 106.630 587.730 ;
    END
  END WriteBack_out[7]
  PIN WriteBack_out[8]
    DIRECTION OUTPUT TRISTATE ;
    USE SIGNAL ;
    ANTENNADIFFAREA 0.795200 ;
    PORT
      LAYER met2 ;
        RECT 399.370 0.000 399.650 4.000 ;
    END
  END WriteBack_out[8]
  PIN WriteBack_out[9]
    DIRECTION OUTPUT TRISTATE ;
    USE SIGNAL ;
    ANTENNADIFFAREA 0.795200 ;
    PORT
      LAYER met3 ;
        RECT 0.000 163.240 4.000 163.840 ;
    END
  END WriteBack_out[9]
  PIN clk
    DIRECTION INPUT ;
    USE SIGNAL ;
    ANTENNAGATEAREA 1.286700 ;
    ANTENNADIFFAREA 0.434700 ;
    PORT
      LAYER met3 ;
        RECT 0.000 516.840 4.000 517.440 ;
    END
  END clk
  PIN reset
    DIRECTION INPUT ;
    USE SIGNAL ;
    ANTENNAGATEAREA 0.196500 ;
    PORT
      LAYER met3 ;
        RECT 573.010 272.040 577.010 272.640 ;
    END
  END reset
  OBS
      LAYER li1 ;
        RECT 5.520 10.795 571.320 576.725 ;
      LAYER met1 ;
        RECT 0.070 8.200 576.770 576.880 ;
      LAYER met2 ;
        RECT 0.650 583.450 19.130 584.530 ;
        RECT 19.970 583.450 35.230 584.530 ;
        RECT 36.070 583.450 54.550 584.530 ;
        RECT 55.390 583.450 70.650 584.530 ;
        RECT 71.490 583.450 86.750 584.530 ;
        RECT 87.590 583.450 106.070 584.530 ;
        RECT 106.910 583.450 122.170 584.530 ;
        RECT 123.010 583.450 141.490 584.530 ;
        RECT 142.330 583.450 157.590 584.530 ;
        RECT 158.430 583.450 176.910 584.530 ;
        RECT 177.750 583.450 193.010 584.530 ;
        RECT 193.850 583.450 209.110 584.530 ;
        RECT 209.950 583.450 228.430 584.530 ;
        RECT 229.270 583.450 244.530 584.530 ;
        RECT 245.370 583.450 263.850 584.530 ;
        RECT 264.690 583.450 279.950 584.530 ;
        RECT 280.790 583.450 299.270 584.530 ;
        RECT 300.110 583.450 315.370 584.530 ;
        RECT 316.210 583.450 331.470 584.530 ;
        RECT 332.310 583.450 350.790 584.530 ;
        RECT 351.630 583.450 366.890 584.530 ;
        RECT 367.730 583.450 386.210 584.530 ;
        RECT 387.050 583.450 402.310 584.530 ;
        RECT 403.150 583.450 421.630 584.530 ;
        RECT 422.470 583.450 437.730 584.530 ;
        RECT 438.570 583.450 453.830 584.530 ;
        RECT 454.670 583.450 473.150 584.530 ;
        RECT 473.990 583.450 489.250 584.530 ;
        RECT 490.090 583.450 508.570 584.530 ;
        RECT 509.410 583.450 524.670 584.530 ;
        RECT 525.510 583.450 543.990 584.530 ;
        RECT 544.830 583.450 560.090 584.530 ;
        RECT 560.930 583.450 576.190 584.530 ;
        RECT 0.100 4.280 576.740 583.450 ;
        RECT 0.650 3.670 15.910 4.280 ;
        RECT 16.750 3.670 32.010 4.280 ;
        RECT 32.850 3.670 51.330 4.280 ;
        RECT 52.170 3.670 67.430 4.280 ;
        RECT 68.270 3.670 86.750 4.280 ;
        RECT 87.590 3.670 102.850 4.280 ;
        RECT 103.690 3.670 122.170 4.280 ;
        RECT 123.010 3.670 138.270 4.280 ;
        RECT 139.110 3.670 154.370 4.280 ;
        RECT 155.210 3.670 173.690 4.280 ;
        RECT 174.530 3.670 189.790 4.280 ;
        RECT 190.630 3.670 209.110 4.280 ;
        RECT 209.950 3.670 225.210 4.280 ;
        RECT 226.050 3.670 244.530 4.280 ;
        RECT 245.370 3.670 260.630 4.280 ;
        RECT 261.470 3.670 276.730 4.280 ;
        RECT 277.570 3.670 296.050 4.280 ;
        RECT 296.890 3.670 312.150 4.280 ;
        RECT 312.990 3.670 331.470 4.280 ;
        RECT 332.310 3.670 347.570 4.280 ;
        RECT 348.410 3.670 366.890 4.280 ;
        RECT 367.730 3.670 382.990 4.280 ;
        RECT 383.830 3.670 399.090 4.280 ;
        RECT 399.930 3.670 418.410 4.280 ;
        RECT 419.250 3.670 434.510 4.280 ;
        RECT 435.350 3.670 453.830 4.280 ;
        RECT 454.670 3.670 469.930 4.280 ;
        RECT 470.770 3.670 489.250 4.280 ;
        RECT 490.090 3.670 505.350 4.280 ;
        RECT 506.190 3.670 521.450 4.280 ;
        RECT 522.290 3.670 540.770 4.280 ;
        RECT 541.610 3.670 556.870 4.280 ;
        RECT 557.710 3.670 576.190 4.280 ;
      LAYER met3 ;
        RECT 3.990 572.240 573.010 576.805 ;
        RECT 4.400 570.840 573.010 572.240 ;
        RECT 3.990 568.840 573.010 570.840 ;
        RECT 3.990 567.440 572.610 568.840 ;
        RECT 3.990 551.840 573.010 567.440 ;
        RECT 4.400 550.440 572.610 551.840 ;
        RECT 3.990 534.840 573.010 550.440 ;
        RECT 4.400 533.440 573.010 534.840 ;
        RECT 3.990 531.440 573.010 533.440 ;
        RECT 3.990 530.040 572.610 531.440 ;
        RECT 3.990 517.840 573.010 530.040 ;
        RECT 4.400 516.440 573.010 517.840 ;
        RECT 3.990 514.440 573.010 516.440 ;
        RECT 3.990 513.040 572.610 514.440 ;
        RECT 3.990 497.440 573.010 513.040 ;
        RECT 4.400 496.040 573.010 497.440 ;
        RECT 3.990 494.040 573.010 496.040 ;
        RECT 3.990 492.640 572.610 494.040 ;
        RECT 3.990 480.440 573.010 492.640 ;
        RECT 4.400 479.040 573.010 480.440 ;
        RECT 3.990 477.040 573.010 479.040 ;
        RECT 3.990 475.640 572.610 477.040 ;
        RECT 3.990 460.040 573.010 475.640 ;
        RECT 4.400 458.640 573.010 460.040 ;
        RECT 3.990 456.640 573.010 458.640 ;
        RECT 3.990 455.240 572.610 456.640 ;
        RECT 3.990 443.040 573.010 455.240 ;
        RECT 4.400 441.640 573.010 443.040 ;
        RECT 3.990 439.640 573.010 441.640 ;
        RECT 3.990 438.240 572.610 439.640 ;
        RECT 3.990 422.640 573.010 438.240 ;
        RECT 4.400 421.240 572.610 422.640 ;
        RECT 3.990 405.640 573.010 421.240 ;
        RECT 4.400 404.240 573.010 405.640 ;
        RECT 3.990 402.240 573.010 404.240 ;
        RECT 3.990 400.840 572.610 402.240 ;
        RECT 3.990 388.640 573.010 400.840 ;
        RECT 4.400 387.240 573.010 388.640 ;
        RECT 3.990 385.240 573.010 387.240 ;
        RECT 3.990 383.840 572.610 385.240 ;
        RECT 3.990 368.240 573.010 383.840 ;
        RECT 4.400 366.840 573.010 368.240 ;
        RECT 3.990 364.840 573.010 366.840 ;
        RECT 3.990 363.440 572.610 364.840 ;
        RECT 3.990 351.240 573.010 363.440 ;
        RECT 4.400 349.840 573.010 351.240 ;
        RECT 3.990 347.840 573.010 349.840 ;
        RECT 3.990 346.440 572.610 347.840 ;
        RECT 3.990 330.840 573.010 346.440 ;
        RECT 4.400 329.440 573.010 330.840 ;
        RECT 3.990 327.440 573.010 329.440 ;
        RECT 3.990 326.040 572.610 327.440 ;
        RECT 3.990 313.840 573.010 326.040 ;
        RECT 4.400 312.440 573.010 313.840 ;
        RECT 3.990 310.440 573.010 312.440 ;
        RECT 3.990 309.040 572.610 310.440 ;
        RECT 3.990 293.440 573.010 309.040 ;
        RECT 4.400 292.040 572.610 293.440 ;
        RECT 3.990 276.440 573.010 292.040 ;
        RECT 4.400 275.040 573.010 276.440 ;
        RECT 3.990 273.040 573.010 275.040 ;
        RECT 3.990 271.640 572.610 273.040 ;
        RECT 3.990 259.440 573.010 271.640 ;
        RECT 4.400 258.040 573.010 259.440 ;
        RECT 3.990 256.040 573.010 258.040 ;
        RECT 3.990 254.640 572.610 256.040 ;
        RECT 3.990 239.040 573.010 254.640 ;
        RECT 4.400 237.640 573.010 239.040 ;
        RECT 3.990 235.640 573.010 237.640 ;
        RECT 3.990 234.240 572.610 235.640 ;
        RECT 3.990 222.040 573.010 234.240 ;
        RECT 4.400 220.640 573.010 222.040 ;
        RECT 3.990 218.640 573.010 220.640 ;
        RECT 3.990 217.240 572.610 218.640 ;
        RECT 3.990 201.640 573.010 217.240 ;
        RECT 4.400 200.240 573.010 201.640 ;
        RECT 3.990 198.240 573.010 200.240 ;
        RECT 3.990 196.840 572.610 198.240 ;
        RECT 3.990 184.640 573.010 196.840 ;
        RECT 4.400 183.240 573.010 184.640 ;
        RECT 3.990 181.240 573.010 183.240 ;
        RECT 3.990 179.840 572.610 181.240 ;
        RECT 3.990 164.240 573.010 179.840 ;
        RECT 4.400 162.840 572.610 164.240 ;
        RECT 3.990 147.240 573.010 162.840 ;
        RECT 4.400 145.840 573.010 147.240 ;
        RECT 3.990 143.840 573.010 145.840 ;
        RECT 3.990 142.440 572.610 143.840 ;
        RECT 3.990 130.240 573.010 142.440 ;
        RECT 4.400 128.840 573.010 130.240 ;
        RECT 3.990 126.840 573.010 128.840 ;
        RECT 3.990 125.440 572.610 126.840 ;
        RECT 3.990 109.840 573.010 125.440 ;
        RECT 4.400 108.440 573.010 109.840 ;
        RECT 3.990 106.440 573.010 108.440 ;
        RECT 3.990 105.040 572.610 106.440 ;
        RECT 3.990 92.840 573.010 105.040 ;
        RECT 4.400 91.440 573.010 92.840 ;
        RECT 3.990 89.440 573.010 91.440 ;
        RECT 3.990 88.040 572.610 89.440 ;
        RECT 3.990 72.440 573.010 88.040 ;
        RECT 4.400 71.040 573.010 72.440 ;
        RECT 3.990 69.040 573.010 71.040 ;
        RECT 3.990 67.640 572.610 69.040 ;
        RECT 3.990 55.440 573.010 67.640 ;
        RECT 4.400 54.040 573.010 55.440 ;
        RECT 3.990 52.040 573.010 54.040 ;
        RECT 3.990 50.640 572.610 52.040 ;
        RECT 3.990 35.040 573.010 50.640 ;
        RECT 4.400 33.640 572.610 35.040 ;
        RECT 3.990 18.040 573.010 33.640 ;
        RECT 4.400 16.640 573.010 18.040 ;
        RECT 3.990 14.640 573.010 16.640 ;
        RECT 3.990 13.240 572.610 14.640 ;
        RECT 3.990 10.715 573.010 13.240 ;
      LAYER met4 ;
        RECT 16.855 11.735 20.640 573.065 ;
        RECT 23.040 11.735 23.940 573.065 ;
        RECT 26.340 11.735 174.240 573.065 ;
        RECT 176.640 11.735 177.540 573.065 ;
        RECT 179.940 11.735 327.840 573.065 ;
        RECT 330.240 11.735 331.140 573.065 ;
        RECT 333.540 11.735 481.440 573.065 ;
        RECT 483.840 11.735 484.740 573.065 ;
        RECT 487.140 11.735 548.945 573.065 ;
      LAYER met5 ;
        RECT 289.460 266.100 337.060 267.700 ;
  END
END top
END LIBRARY

